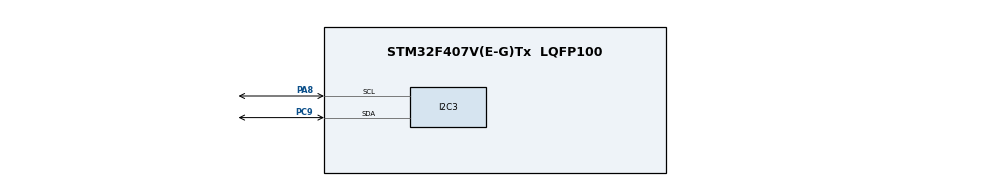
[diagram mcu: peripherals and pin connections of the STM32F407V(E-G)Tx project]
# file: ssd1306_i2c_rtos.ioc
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FREERTOS.Tasks01=defaultTask,24,128,StartDefaultTask,Default,NULL,Dynamic,NULL,NULL
FREERTOS.configUSE_NEWLIB_REENTRANT=1
Mcu.Family=STM32F4
Mcu.Name=STM32F407V(E-G)Tx
Mcu.Package=LQFP100
NVIC.PriorityGroup=NVIC_PRIORITYGROUP_4
NVIC.TIM6_DAC_IRQn=true\:15\:0\:false\:false\:true\:false\:false\:true
NVIC.TimeBase=TIM6_DAC_IRQn
NVIC.TimeBaseIP=TIM6
PA8.Mode=I2C
PA8.Signal=I2C3_SCL
PC9.Mode=I2C
PC9.Signal=I2C3_SDA
PH0-OSC_IN.Mode=HSE-External-Oscillator
PH0-OSC_IN.Signal=RCC_OSC_IN
PH1-OSC_OUT.Mode=HSE-External-Oscillator
PH1-OSC_OUT.Signal=RCC_OSC_OUT
ProjectManager.HeapSize=0x200
ProjectManager.StackSize=0x400
ProjectManager.TargetToolchain=STM32CubeIDE
RCC.48MHZClocksFreq_Value=14285714.285714285
RCC.AHBFreq_Value=50000000
RCC.APB1CLKDivider=RCC_HCLK_DIV4
RCC.APB1Freq_Value=12500000
RCC.APB1TimFreq_Value=25000000
RCC.APB2CLKDivider=RCC_HCLK_DIV2
RCC.APB2Freq_Value=25000000
RCC.APB2TimFreq_Value=50000000
RCC.CortexFreq_Value=50000000
RCC.HCLKFreq_Value=50000000
RCC.HSE_VALUE=8000000
RCC.HSI_VALUE=16000000
RCC.PLLM=8
RCC.PLLN=100
RCC.PLLQ=7
RCC.PLLSourceVirtual=RCC_PLLSOURCE_HSE
RCC.SYSCLKFreq_VALUE=50000000
RCC.SYSCLKSource=RCC_SYSCLKSOURCE_PLLCLK
RCC.VCOOutputFreq_Value=100000000
VP_FREERTOS_VS_CMSIS_V2.Mode=CMSIS_V2
VP_SYS_VS_tim6.Mode=TIM6
board=STM32F407G-DISC1

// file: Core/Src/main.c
/* USER CODE BEGIN Header */
/**
  ******************************************************************************
  * @file           : main.c
  * @brief          : Main program body
  ******************************************************************************
  * @attention
  *
  * <h2><center>&copy; Copyright (c) 2021 STMicroelectronics.
  * All rights reserved.</center></h2>
  *
  * This software component is licensed by ST under BSD 3-Clause license,
  * the "License"; You may not use this file except in compliance with the
  * License. You may obtain a copy of the License at:
  *                        opensource.org/licenses/BSD-3-Clause
  *
  ******************************************************************************
  */
/* USER CODE END Header */
#include "main.h"
#include "cmsis_os.h"

/* USER CODE BEGIN Includes */
#include <stdint.h>
#include "ssd1306.h"
#include "app_display.h"
#include "filas_rtos.h"
#include "teste_escrita.h"

/* USER CODE END Includes */

I2C_HandleTypeDef hi2c3;

/* Definitions for defaultTask */
osThreadId_t defaultTaskHandle;
const osThreadAttr_t defaultTask_attributes = {
  .name = "defaultTask",
  .stack_size = 128 * 4,
  .priority = (osPriority_t) osPriorityNormal,
};

void SystemClock_Config(void);
static void MX_GPIO_Init(void);
static void MX_I2C3_Init(void);
void StartDefaultTask(void *argument);

int main(void)
{

  /* MCU Configuration--------------------------------------------------------*/

  /* Reset of all peripherals, Initializes the Flash interface and the Systick. */
  HAL_Init();

  /* Configure the system clock */
  SystemClock_Config();

  /* Initialize all configured peripherals */
  MX_GPIO_Init();
  MX_I2C3_Init();
  /* USER CODE BEGIN 2 */

  /* Inicializa a função rtos em app_display   */
  criar_filas();
  start_rtos();
  start_wTask();

  /* USER CODE END 2 */

  /* Init scheduler */
  osKernelInitialize();

  /* Create the thread(s) */
  /* creation of defaultTask */
  defaultTaskHandle = osThreadNew(StartDefaultTask, NULL, &defaultTask_attributes);

  /* Start scheduler */
  osKernelStart();

  /* We should never get here as control is now taken by the scheduler */
  /* Infinite loop */
  while (1)
  {

  }
}

void SystemClock_Config(void)
{
  RCC_OscInitTypeDef RCC_OscInitStruct = {0};
  RCC_ClkInitTypeDef RCC_ClkInitStruct = {0};

  /** Configure the main internal regulator output voltage
  */
  __HAL_RCC_PWR_CLK_ENABLE();
  __HAL_PWR_VOLTAGESCALING_CONFIG(PWR_REGULATOR_VOLTAGE_SCALE1);
  /** Initializes the RCC Oscillators according to the specified parameters
  * in the RCC_OscInitTypeDef structure.
  */
  RCC_OscInitStruct.OscillatorType = RCC_OSCILLATORTYPE_HSE;
  RCC_OscInitStruct.HSEState = RCC_HSE_ON;
  RCC_OscInitStruct.PLL.PLLState = RCC_PLL_ON;
  RCC_OscInitStruct.PLL.PLLSource = RCC_PLLSOURCE_HSE;
  RCC_OscInitStruct.PLL.PLLM = 4;
  RCC_OscInitStruct.PLL.PLLN = 168;
  RCC_OscInitStruct.PLL.PLLP = RCC_PLLP_DIV2;
  RCC_OscInitStruct.PLL.PLLQ = 7;
  if (HAL_RCC_OscConfig(&RCC_OscInitStruct) != HAL_OK)
  {
    Error_Handler();
  }
  /** Initializes the CPU, AHB and APB buses clocks
  */
  RCC_ClkInitStruct.ClockType = RCC_CLOCKTYPE_HCLK|RCC_CLOCKTYPE_SYSCLK
                              |RCC_CLOCKTYPE_PCLK1|RCC_CLOCKTYPE_PCLK2;
  RCC_ClkInitStruct.SYSCLKSource = RCC_SYSCLKSOURCE_PLLCLK;
  RCC_ClkInitStruct.AHBCLKDivider = RCC_SYSCLK_DIV1;
  RCC_ClkInitStruct.APB1CLKDivider = RCC_HCLK_DIV4;
  RCC_ClkInitStruct.APB2CLKDivider = RCC_HCLK_DIV2;

  if (HAL_RCC_ClockConfig(&RCC_ClkInitStruct, FLASH_LATENCY_5) != HAL_OK)
  {
    Error_Handler();
  }
}

static void MX_I2C3_Init(void)
{

  hi2c3.Instance = I2C3;
  hi2c3.Init.ClockSpeed = 100000;
  hi2c3.Init.DutyCycle = I2C_DUTYCYCLE_2;
  hi2c3.Init.OwnAddress1 = 0;
  hi2c3.Init.AddressingMode = I2C_ADDRESSINGMODE_7BIT;
  hi2c3.Init.DualAddressMode = I2C_DUALADDRESS_DISABLE;
  hi2c3.Init.OwnAddress2 = 0;
  hi2c3.Init.GeneralCallMode = I2C_GENERALCALL_DISABLE;
  hi2c3.Init.NoStretchMode = I2C_NOSTRETCH_DISABLE;
  if (HAL_I2C_Init(&hi2c3) != HAL_OK)
  {
    Error_Handler();
  }

}

static void MX_GPIO_Init(void)
{

  /* GPIO Ports Clock Enable */
  __HAL_RCC_GPIOH_CLK_ENABLE();
  __HAL_RCC_GPIOC_CLK_ENABLE();
  __HAL_RCC_GPIOA_CLK_ENABLE();

}

void StartDefaultTask(void *argument)
{
  for(;;)
  {
    osDelay(1);
  }
}

void HAL_TIM_PeriodElapsedCallback(TIM_HandleTypeDef *htim)
{
  if (htim->Instance == TIM6) {
    HAL_IncTick();
  }
}

void Error_Handler(void)
{
  __disable_irq();
  while (1)
  {
  }
}

/************************ (C) COPYRIGHT STMicroelectronics *****END OF FILE****/
